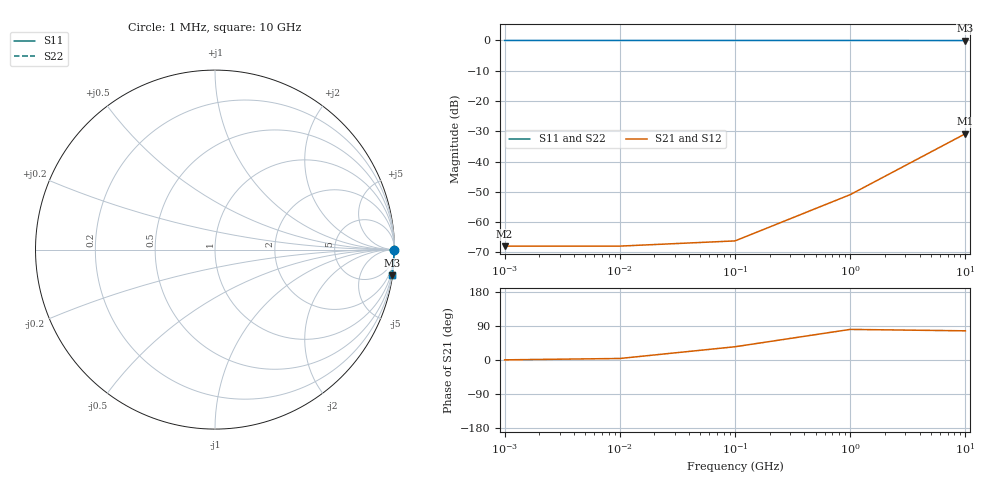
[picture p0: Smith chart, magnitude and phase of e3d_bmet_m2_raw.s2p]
! Sonnet Data File
! From: em Version : 18.53-Lite
! From Project: e3d_bmet_m2
! Data is NOT De-embedded
! Data File Written: 10/12/2026 13:46:06
!< HDATE 10/12/2026 13:46:06
!< MDATE 10/12/2026 13:46:06
# GHZ S RI R 50.00000
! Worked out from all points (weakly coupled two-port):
!   5 points, 1 MHz to 10 GHz, reference 50 ohm
!   highest |S21| = -30.81 dB at 10 GHz (marker M1); lowest = -68.0 dB at 1 MHz (marker M2)
!   lowest |S11| = 0.0 dB at 10 GHz (marker M3), VSWR 467.45, Z = 20.8 - j695 ohm
!   |S11| at or under -10 dB: nowhere
!   |S22| runs from 0.0 to 0.0 dB; largest |S21 - S12| = 3.1e-13
0.001  0.9996 -1.42e-05  0.0004 2.8e-06  0.0004 2.8e-06  0.9996 -1.42e-05
0.01  0.9996 -0.000142  0.0004 2.8e-05  0.0004 2.8e-05  0.9996 -0.000142
0.1  0.9996 -0.00142  0.0004 0.00028  0.0004 0.00028  0.9996 -0.00142
1  0.9995 -0.0142  0.000457 0.0028  0.000457 0.0028  0.9995 -0.0142
10  0.9855 -0.1425  0.00649 0.0281  0.00649 0.0281  0.9855 -0.1425
